VERSION 5.7 ;
  NOWIREEXTENSIONATPIN ON ;
  DIVIDERCHAR "/" ;
  BUSBITCHARS "[]" ;
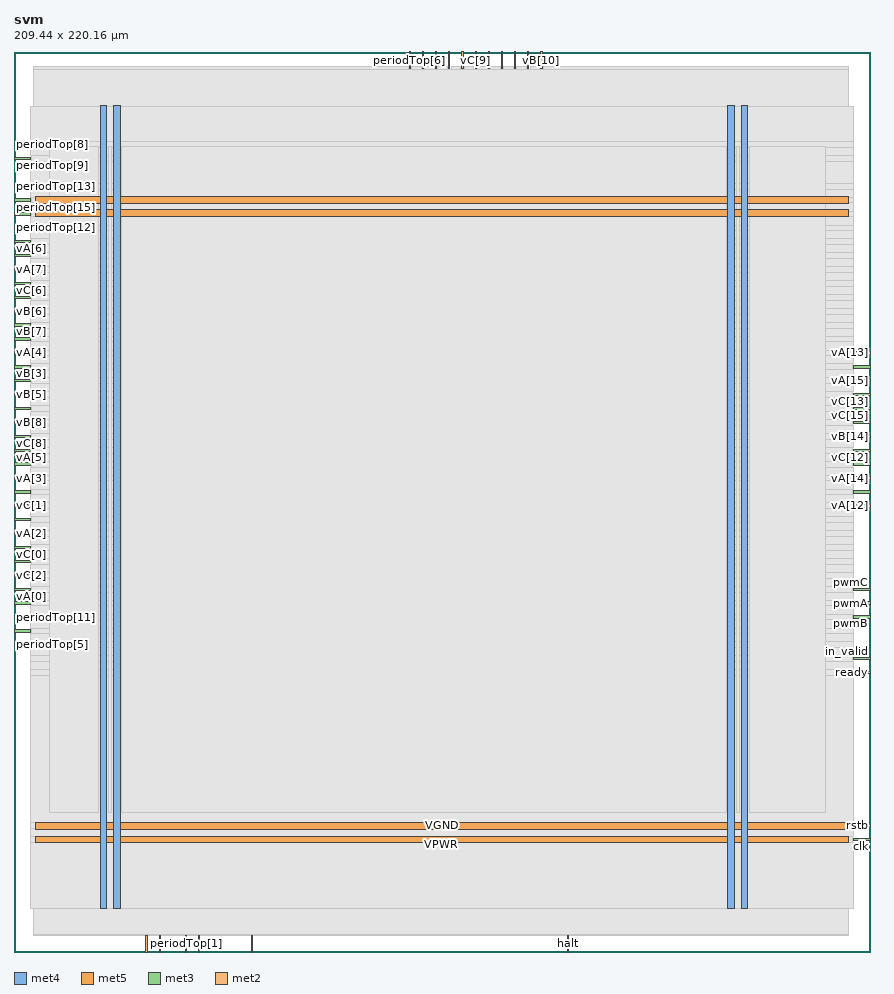
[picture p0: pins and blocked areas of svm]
MACRO svm
  CLASS BLOCK ;
  FOREIGN svm ;
  ORIGIN 0.000 0.000 ;
  SIZE 209.440 BY 220.160 ;
  PIN VGND
    DIRECTION INOUT ;
    USE GROUND ;
    PORT
      LAYER met4 ;
        RECT 24.340 10.640 25.940 206.960 ;
    END
    PORT
      LAYER met4 ;
        RECT 177.940 10.640 179.540 206.960 ;
    END
    PORT
      LAYER met5 ;
        RECT 5.280 30.030 204.020 31.630 ;
    END
    PORT
      LAYER met5 ;
        RECT 5.280 183.210 204.020 184.810 ;
    END
  END VGND
  PIN VPWR
    DIRECTION INOUT ;
    USE POWER ;
    PORT
      LAYER met4 ;
        RECT 21.040 10.640 22.640 206.960 ;
    END
    PORT
      LAYER met4 ;
        RECT 174.640 10.640 176.240 206.960 ;
    END
    PORT
      LAYER met5 ;
        RECT 5.280 26.730 204.020 28.330 ;
    END
    PORT
      LAYER met5 ;
        RECT 5.280 179.910 204.020 181.510 ;
    END
  END VPWR
  PIN clk
    DIRECTION INPUT ;
    USE SIGNAL ;
    ANTENNAGATEAREA 0.852000 ;
    PORT
      LAYER met3 ;
        RECT 205.440 27.240 209.440 27.840 ;
    END
  END clk
  PIN halt
    DIRECTION OUTPUT ;
    USE SIGNAL ;
    ANTENNADIFFAREA 0.795200 ;
    PORT
      LAYER met2 ;
        RECT 135.330 0.000 135.610 4.000 ;
    END
  END halt
  PIN in_valid
    DIRECTION INPUT ;
    USE SIGNAL ;
    ANTENNAGATEAREA 0.196500 ;
    PORT
      LAYER met3 ;
        RECT 205.440 71.440 209.440 72.040 ;
    END
  END in_valid
  PIN periodTop[0]
    DIRECTION INPUT ;
    USE SIGNAL ;
    ANTENNAGATEAREA 0.213000 ;
    PORT
      LAYER met2 ;
        RECT 58.050 0.000 58.330 4.000 ;
    END
  END periodTop[0]
  PIN periodTop[10]
    DIRECTION INPUT ;
    USE SIGNAL ;
    ANTENNAGATEAREA 0.159000 ;
    PORT
      LAYER met3 ;
        RECT 0.000 78.240 4.000 78.840 ;
    END
  END periodTop[10]
  PIN periodTop[11]
    DIRECTION INPUT ;
    USE SIGNAL ;
    ANTENNAGATEAREA 0.213000 ;
    PORT
      LAYER met3 ;
        RECT 0.000 81.640 4.000 82.240 ;
    END
  END periodTop[11]
  PIN periodTop[12]
    DIRECTION INPUT ;
    USE SIGNAL ;
    ANTENNAGATEAREA 0.196500 ;
    PORT
      LAYER met3 ;
        RECT 0.000 176.840 4.000 177.440 ;
    END
  END periodTop[12]
  PIN periodTop[13]
    DIRECTION INPUT ;
    USE SIGNAL ;
    ANTENNAGATEAREA 0.213000 ;
    PORT
      LAYER met3 ;
        RECT 0.000 187.040 4.000 187.640 ;
    END
  END periodTop[13]
  PIN periodTop[14]
    DIRECTION INPUT ;
    USE SIGNAL ;
    ANTENNAGATEAREA 0.213000 ;
    PORT
      LAYER met3 ;
        RECT 0.000 183.640 4.000 184.240 ;
    END
  END periodTop[14]
  PIN periodTop[15]
    DIRECTION INPUT ;
    USE SIGNAL ;
    ANTENNAGATEAREA 0.196500 ;
    PORT
      LAYER met3 ;
        RECT 0.000 180.240 4.000 180.840 ;
    END
  END periodTop[15]
  PIN periodTop[1]
    DIRECTION INPUT ;
    USE SIGNAL ;
    ANTENNAGATEAREA 0.196500 ;
    PORT
      LAYER met2 ;
        RECT 41.950 0.000 42.230 4.000 ;
    END
  END periodTop[1]
  PIN periodTop[2]
    DIRECTION INPUT ;
    USE SIGNAL ;
    ANTENNAGATEAREA 0.196500 ;
    PORT
      LAYER met2 ;
        RECT 45.170 0.000 45.450 4.000 ;
    END
  END periodTop[2]
  PIN periodTop[3]
    DIRECTION INPUT ;
    USE SIGNAL ;
    ANTENNAGATEAREA 0.196500 ;
    PORT
      LAYER met2 ;
        RECT 35.510 0.000 35.790 4.000 ;
    END
  END periodTop[3]
  PIN periodTop[4]
    DIRECTION INPUT ;
    USE SIGNAL ;
    ANTENNAGATEAREA 0.159000 ;
    PORT
      LAYER met2 ;
        RECT 32.290 0.000 32.570 4.000 ;
    END
  END periodTop[4]
  PIN periodTop[5]
    DIRECTION INPUT ;
    USE SIGNAL ;
    ANTENNAGATEAREA 0.213000 ;
    PORT
      LAYER met3 ;
        RECT 0.000 74.840 4.000 75.440 ;
    END
  END periodTop[5]
  PIN periodTop[6]
    DIRECTION INPUT ;
    USE SIGNAL ;
    ANTENNAGATEAREA 0.126000 ;
    PORT
      LAYER met2 ;
        RECT 96.690 216.160 96.970 220.160 ;
    END
  END periodTop[6]
  PIN periodTop[7]
    DIRECTION INPUT ;
    USE SIGNAL ;
    ANTENNAGATEAREA 0.126000 ;
    PORT
      LAYER met2 ;
        RECT 99.910 216.160 100.190 220.160 ;
    END
  END periodTop[7]
  PIN periodTop[8]
    DIRECTION INPUT ;
    USE SIGNAL ;
    ANTENNAGATEAREA 0.126000 ;
    PORT
      LAYER met3 ;
        RECT 0.000 197.240 4.000 197.840 ;
    END
  END periodTop[8]
  PIN periodTop[9]
    DIRECTION INPUT ;
    USE SIGNAL ;
    ANTENNAGATEAREA 0.126000 ;
    PORT
      LAYER met3 ;
        RECT 0.000 193.840 4.000 194.440 ;
    END
  END periodTop[9]
  PIN pwmA
    DIRECTION OUTPUT ;
    USE SIGNAL ;
    ANTENNADIFFAREA 0.795200 ;
    PORT
      LAYER met3 ;
        RECT 205.440 85.040 209.440 85.640 ;
    END
  END pwmA
  PIN pwmB
    DIRECTION OUTPUT ;
    USE SIGNAL ;
    ANTENNADIFFAREA 0.795200 ;
    PORT
      LAYER met3 ;
        RECT 205.440 81.640 209.440 82.240 ;
    END
  END pwmB
  PIN pwmC
    DIRECTION OUTPUT ;
    USE SIGNAL ;
    ANTENNADIFFAREA 0.445500 ;
    PORT
      LAYER met3 ;
        RECT 205.440 88.440 209.440 89.040 ;
    END
  END pwmC
  PIN ready
    DIRECTION OUTPUT ;
    USE SIGNAL ;
    ANTENNADIFFAREA 0.795200 ;
    PORT
      LAYER met3 ;
        RECT 205.440 68.040 209.440 68.640 ;
    END
  END ready
  PIN rstb
    DIRECTION INPUT ;
    USE SIGNAL ;
    ANTENNAGATEAREA 0.196500 ;
    PORT
      LAYER met3 ;
        RECT 205.440 30.640 209.440 31.240 ;
    END
  END rstb
  PIN vA[0]
    DIRECTION INPUT ;
    USE SIGNAL ;
    ANTENNAGATEAREA 0.196500 ;
    PORT
      LAYER met3 ;
        RECT 0.000 85.040 4.000 85.640 ;
    END
  END vA[0]
  PIN vA[10]
    DIRECTION INPUT ;
    USE SIGNAL ;
    ANTENNAGATEAREA 0.196500 ;
    PORT
      LAYER met2 ;
        RECT 103.130 216.160 103.410 220.160 ;
    END
  END vA[10]
  PIN vA[11]
    DIRECTION INPUT ;
    USE SIGNAL ;
    ANTENNAGATEAREA 0.196500 ;
    PORT
      LAYER met2 ;
        RECT 116.010 216.160 116.290 220.160 ;
    END
  END vA[11]
  PIN vA[12]
    DIRECTION INPUT ;
    USE SIGNAL ;
    ANTENNAGATEAREA 0.196500 ;
    PORT
      LAYER met3 ;
        RECT 205.440 108.840 209.440 109.440 ;
    END
  END vA[12]
  PIN vA[13]
    DIRECTION INPUT ;
    USE SIGNAL ;
    ANTENNAGATEAREA 0.196500 ;
    PORT
      LAYER met3 ;
        RECT 205.440 146.240 209.440 146.840 ;
    END
  END vA[13]
  PIN vA[14]
    DIRECTION INPUT ;
    USE SIGNAL ;
    ANTENNAGATEAREA 0.196500 ;
    PORT
      LAYER met3 ;
        RECT 205.440 115.640 209.440 116.240 ;
    END
  END vA[14]
  PIN vA[15]
    DIRECTION INPUT ;
    USE SIGNAL ;
    ANTENNAGATEAREA 0.196500 ;
    PORT
      LAYER met3 ;
        RECT 205.440 139.440 209.440 140.040 ;
    END
  END vA[15]
  PIN vA[1]
    DIRECTION INPUT ;
    USE SIGNAL ;
    ANTENNAGATEAREA 0.196500 ;
    PORT
      LAYER met3 ;
        RECT 0.000 112.240 4.000 112.840 ;
    END
  END vA[1]
  PIN vA[2]
    DIRECTION INPUT ;
    USE SIGNAL ;
    ANTENNAGATEAREA 0.196500 ;
    PORT
      LAYER met3 ;
        RECT 0.000 102.040 4.000 102.640 ;
    END
  END vA[2]
  PIN vA[3]
    DIRECTION INPUT ;
    USE SIGNAL ;
    ANTENNAGATEAREA 0.196500 ;
    PORT
      LAYER met3 ;
        RECT 0.000 115.640 4.000 116.240 ;
    END
  END vA[3]
  PIN vA[4]
    DIRECTION INPUT ;
    USE SIGNAL ;
    ANTENNAGATEAREA 0.196500 ;
    PORT
      LAYER met3 ;
        RECT 0.000 146.240 4.000 146.840 ;
    END
  END vA[4]
  PIN vA[5]
    DIRECTION INPUT ;
    USE SIGNAL ;
    ANTENNAGATEAREA 0.196500 ;
    PORT
      LAYER met3 ;
        RECT 0.000 119.040 4.000 119.640 ;
    END
  END vA[5]
  PIN vA[6]
    DIRECTION INPUT ;
    USE SIGNAL ;
    ANTENNAGATEAREA 0.196500 ;
    PORT
      LAYER met3 ;
        RECT 0.000 173.440 4.000 174.040 ;
    END
  END vA[6]
  PIN vA[7]
    DIRECTION INPUT ;
    USE SIGNAL ;
    ANTENNAGATEAREA 0.196500 ;
    PORT
      LAYER met3 ;
        RECT 0.000 166.640 4.000 167.240 ;
    END
  END vA[7]
  PIN vA[8]
    DIRECTION INPUT ;
    USE SIGNAL ;
    ANTENNAGATEAREA 0.196500 ;
    PORT
      LAYER met3 ;
        RECT 0.000 122.440 4.000 123.040 ;
    END
  END vA[8]
  PIN vA[9]
    DIRECTION INPUT ;
    USE SIGNAL ;
    ANTENNAGATEAREA 0.196500 ;
    PORT
      LAYER met2 ;
        RECT 106.350 216.160 106.630 220.160 ;
    END
  END vA[9]
  PIN vB[0]
    DIRECTION INPUT ;
    USE SIGNAL ;
    ANTENNAGATEAREA 0.196500 ;
    PORT
      LAYER met3 ;
        RECT 0.000 88.440 4.000 89.040 ;
    END
  END vB[0]
  PIN vB[10]
    DIRECTION INPUT ;
    USE SIGNAL ;
    ANTENNAGATEAREA 0.196500 ;
    PORT
      LAYER met2 ;
        RECT 128.890 216.160 129.170 220.160 ;
    END
  END vB[10]
  PIN vB[11]
    DIRECTION INPUT ;
    USE SIGNAL ;
    ANTENNAGATEAREA 0.196500 ;
    PORT
      LAYER met2 ;
        RECT 119.230 216.160 119.510 220.160 ;
    END
  END vB[11]
  PIN vB[12]
    DIRECTION INPUT ;
    USE SIGNAL ;
    ANTENNAGATEAREA 0.196500 ;
    PORT
      LAYER met3 ;
        RECT 205.440 112.240 209.440 112.840 ;
    END
  END vB[12]
  PIN vB[13]
    DIRECTION INPUT ;
    USE SIGNAL ;
    ANTENNAGATEAREA 0.196500 ;
    PORT
      LAYER met3 ;
        RECT 205.440 142.840 209.440 143.440 ;
    END
  END vB[13]
  PIN vB[14]
    DIRECTION INPUT ;
    USE SIGNAL ;
    ANTENNAGATEAREA 0.196500 ;
    PORT
      LAYER met3 ;
        RECT 205.440 125.840 209.440 126.440 ;
    END
  END vB[14]
  PIN vB[15]
    DIRECTION INPUT ;
    USE SIGNAL ;
    ANTENNAGATEAREA 0.196500 ;
    PORT
      LAYER met3 ;
        RECT 205.440 132.640 209.440 133.240 ;
    END
  END vB[15]
  PIN vB[1]
    DIRECTION INPUT ;
    USE SIGNAL ;
    ANTENNAGATEAREA 0.196500 ;
    PORT
      LAYER met3 ;
        RECT 0.000 105.440 4.000 106.040 ;
    END
  END vB[1]
  PIN vB[2]
    DIRECTION INPUT ;
    USE SIGNAL ;
    ANTENNAGATEAREA 0.196500 ;
    PORT
      LAYER met3 ;
        RECT 0.000 95.240 4.000 95.840 ;
    END
  END vB[2]
  PIN vB[3]
    DIRECTION INPUT ;
    USE SIGNAL ;
    ANTENNAGATEAREA 0.196500 ;
    PORT
      LAYER met3 ;
        RECT 0.000 142.840 4.000 143.440 ;
    END
  END vB[3]
  PIN vB[4]
    DIRECTION INPUT ;
    USE SIGNAL ;
    ANTENNAGATEAREA 0.196500 ;
    PORT
      LAYER met3 ;
        RECT 0.000 170.040 4.000 170.640 ;
    END
  END vB[4]
  PIN vB[5]
    DIRECTION INPUT ;
    USE SIGNAL ;
    ANTENNAGATEAREA 0.196500 ;
    PORT
      LAYER met3 ;
        RECT 0.000 136.040 4.000 136.640 ;
    END
  END vB[5]
  PIN vB[6]
    DIRECTION INPUT ;
    USE SIGNAL ;
    ANTENNAGATEAREA 0.196500 ;
    PORT
      LAYER met3 ;
        RECT 0.000 156.440 4.000 157.040 ;
    END
  END vB[6]
  PIN vB[7]
    DIRECTION INPUT ;
    USE SIGNAL ;
    ANTENNAGATEAREA 0.196500 ;
    PORT
      LAYER met3 ;
        RECT 0.000 153.040 4.000 153.640 ;
    END
  END vB[7]
  PIN vB[8]
    DIRECTION INPUT ;
    USE SIGNAL ;
    ANTENNAGATEAREA 0.196500 ;
    PORT
      LAYER met3 ;
        RECT 0.000 129.240 4.000 129.840 ;
    END
  END vB[8]
  PIN vB[9]
    DIRECTION INPUT ;
    USE SIGNAL ;
    ANTENNAGATEAREA 0.196500 ;
    PORT
      LAYER met2 ;
        RECT 109.570 216.160 109.850 220.160 ;
    END
  END vB[9]
  PIN vC[0]
    DIRECTION INPUT ;
    USE SIGNAL ;
    ANTENNAGATEAREA 0.495000 ;
    PORT
      LAYER met3 ;
        RECT 0.000 98.640 4.000 99.240 ;
    END
  END vC[0]
  PIN vC[10]
    DIRECTION INPUT ;
    USE SIGNAL ;
    ANTENNAGATEAREA 0.495000 ;
    PORT
      LAYER met2 ;
        RECT 122.450 216.160 122.730 220.160 ;
    END
  END vC[10]
  PIN vC[11]
    DIRECTION INPUT ;
    USE SIGNAL ;
    ANTENNAGATEAREA 0.196500 ;
    PORT
      LAYER met2 ;
        RECT 125.670 216.160 125.950 220.160 ;
    END
  END vC[11]
  PIN vC[12]
    DIRECTION INPUT ;
    USE SIGNAL ;
    ANTENNAGATEAREA 0.196500 ;
    PORT
      LAYER met3 ;
        RECT 205.440 119.040 209.440 119.640 ;
    END
  END vC[12]
  PIN vC[13]
    DIRECTION INPUT ;
    USE SIGNAL ;
    ANTENNAGATEAREA 0.196500 ;
    PORT
      LAYER met3 ;
        RECT 205.440 136.040 209.440 136.640 ;
    END
  END vC[13]
  PIN vC[14]
    DIRECTION INPUT ;
    USE SIGNAL ;
    ANTENNAGATEAREA 0.196500 ;
    PORT
      LAYER met3 ;
        RECT 205.440 122.440 209.440 123.040 ;
    END
  END vC[14]
  PIN vC[15]
    DIRECTION INPUT ;
    USE SIGNAL ;
    ANTENNAGATEAREA 0.196500 ;
    PORT
      LAYER met3 ;
        RECT 205.440 129.240 209.440 129.840 ;
    END
  END vC[15]
  PIN vC[1]
    DIRECTION INPUT ;
    USE SIGNAL ;
    ANTENNAGATEAREA 0.196500 ;
    PORT
      LAYER met3 ;
        RECT 0.000 108.840 4.000 109.440 ;
    END
  END vC[1]
  PIN vC[2]
    DIRECTION INPUT ;
    USE SIGNAL ;
    ANTENNAGATEAREA 0.196500 ;
    PORT
      LAYER met3 ;
        RECT 0.000 91.840 4.000 92.440 ;
    END
  END vC[2]
  PIN vC[3]
    DIRECTION INPUT ;
    USE SIGNAL ;
    ANTENNAGATEAREA 0.196500 ;
    PORT
      LAYER met3 ;
        RECT 0.000 139.440 4.000 140.040 ;
    END
  END vC[3]
  PIN vC[4]
    DIRECTION INPUT ;
    USE SIGNAL ;
    ANTENNAGATEAREA 0.495000 ;
    PORT
      LAYER met3 ;
        RECT 0.000 149.640 4.000 150.240 ;
    END
  END vC[4]
  PIN vC[5]
    DIRECTION INPUT ;
    USE SIGNAL ;
    ANTENNAGATEAREA 0.196500 ;
    PORT
      LAYER met3 ;
        RECT 0.000 132.640 4.000 133.240 ;
    END
  END vC[5]
  PIN vC[6]
    DIRECTION INPUT ;
    USE SIGNAL ;
    ANTENNAGATEAREA 0.196500 ;
    PORT
      LAYER met3 ;
        RECT 0.000 159.840 4.000 160.440 ;
    END
  END vC[6]
  PIN vC[7]
    DIRECTION INPUT ;
    USE SIGNAL ;
    ANTENNAGATEAREA 0.196500 ;
    PORT
      LAYER met3 ;
        RECT 0.000 163.240 4.000 163.840 ;
    END
  END vC[7]
  PIN vC[8]
    DIRECTION INPUT ;
    USE SIGNAL ;
    ANTENNAGATEAREA 0.196500 ;
    PORT
      LAYER met3 ;
        RECT 0.000 125.840 4.000 126.440 ;
    END
  END vC[8]
  PIN vC[9]
    DIRECTION INPUT ;
    USE SIGNAL ;
    ANTENNAGATEAREA 0.495000 ;
    PORT
      LAYER met2 ;
        RECT 112.790 216.160 113.070 220.160 ;
    END
  END vC[9]
  OBS
      LAYER li1 ;
        RECT 5.520 10.795 203.780 206.805 ;
      LAYER met1 ;
        RECT 4.670 10.640 204.170 206.960 ;
      LAYER met2 ;
        RECT 4.690 215.880 96.410 216.650 ;
        RECT 97.250 215.880 99.630 216.650 ;
        RECT 100.470 215.880 102.850 216.650 ;
        RECT 103.690 215.880 106.070 216.650 ;
        RECT 106.910 215.880 109.290 216.650 ;
        RECT 110.130 215.880 112.510 216.650 ;
        RECT 113.350 215.880 115.730 216.650 ;
        RECT 116.570 215.880 118.950 216.650 ;
        RECT 119.790 215.880 122.170 216.650 ;
        RECT 123.010 215.880 125.390 216.650 ;
        RECT 126.230 215.880 128.610 216.650 ;
        RECT 129.450 215.880 204.150 216.650 ;
        RECT 4.690 4.280 204.150 215.880 ;
        RECT 4.690 4.000 32.010 4.280 ;
        RECT 32.850 4.000 35.230 4.280 ;
        RECT 36.070 4.000 41.670 4.280 ;
        RECT 42.510 4.000 44.890 4.280 ;
        RECT 45.730 4.000 57.770 4.280 ;
        RECT 58.610 4.000 135.050 4.280 ;
        RECT 135.890 4.000 204.150 4.280 ;
      LAYER met3 ;
        RECT 3.990 198.240 205.440 206.885 ;
        RECT 4.400 196.840 205.440 198.240 ;
        RECT 3.990 194.840 205.440 196.840 ;
        RECT 4.400 193.440 205.440 194.840 ;
        RECT 3.990 188.040 205.440 193.440 ;
        RECT 4.400 186.640 205.440 188.040 ;
        RECT 3.990 184.640 205.440 186.640 ;
        RECT 4.400 183.240 205.440 184.640 ;
        RECT 3.990 181.240 205.440 183.240 ;
        RECT 4.400 179.840 205.440 181.240 ;
        RECT 3.990 177.840 205.440 179.840 ;
        RECT 4.400 176.440 205.440 177.840 ;
        RECT 3.990 174.440 205.440 176.440 ;
        RECT 4.400 173.040 205.440 174.440 ;
        RECT 3.990 171.040 205.440 173.040 ;
        RECT 4.400 169.640 205.440 171.040 ;
        RECT 3.990 167.640 205.440 169.640 ;
        RECT 4.400 166.240 205.440 167.640 ;
        RECT 3.990 164.240 205.440 166.240 ;
        RECT 4.400 162.840 205.440 164.240 ;
        RECT 3.990 160.840 205.440 162.840 ;
        RECT 4.400 159.440 205.440 160.840 ;
        RECT 3.990 157.440 205.440 159.440 ;
        RECT 4.400 156.040 205.440 157.440 ;
        RECT 3.990 154.040 205.440 156.040 ;
        RECT 4.400 152.640 205.440 154.040 ;
        RECT 3.990 150.640 205.440 152.640 ;
        RECT 4.400 149.240 205.440 150.640 ;
        RECT 3.990 147.240 205.440 149.240 ;
        RECT 4.400 145.840 205.040 147.240 ;
        RECT 3.990 143.840 205.440 145.840 ;
        RECT 4.400 142.440 205.040 143.840 ;
        RECT 3.990 140.440 205.440 142.440 ;
        RECT 4.400 139.040 205.040 140.440 ;
        RECT 3.990 137.040 205.440 139.040 ;
        RECT 4.400 135.640 205.040 137.040 ;
        RECT 3.990 133.640 205.440 135.640 ;
        RECT 4.400 132.240 205.040 133.640 ;
        RECT 3.990 130.240 205.440 132.240 ;
        RECT 4.400 128.840 205.040 130.240 ;
        RECT 3.990 126.840 205.440 128.840 ;
        RECT 4.400 125.440 205.040 126.840 ;
        RECT 3.990 123.440 205.440 125.440 ;
        RECT 4.400 122.040 205.040 123.440 ;
        RECT 3.990 120.040 205.440 122.040 ;
        RECT 4.400 118.640 205.040 120.040 ;
        RECT 3.990 116.640 205.440 118.640 ;
        RECT 4.400 115.240 205.040 116.640 ;
        RECT 3.990 113.240 205.440 115.240 ;
        RECT 4.400 111.840 205.040 113.240 ;
        RECT 3.990 109.840 205.440 111.840 ;
        RECT 4.400 108.440 205.040 109.840 ;
        RECT 3.990 106.440 205.440 108.440 ;
        RECT 4.400 105.040 205.440 106.440 ;
        RECT 3.990 103.040 205.440 105.040 ;
        RECT 4.400 101.640 205.440 103.040 ;
        RECT 3.990 99.640 205.440 101.640 ;
        RECT 4.400 98.240 205.440 99.640 ;
        RECT 3.990 96.240 205.440 98.240 ;
        RECT 4.400 94.840 205.440 96.240 ;
        RECT 3.990 92.840 205.440 94.840 ;
        RECT 4.400 91.440 205.440 92.840 ;
        RECT 3.990 89.440 205.440 91.440 ;
        RECT 4.400 88.040 205.040 89.440 ;
        RECT 3.990 86.040 205.440 88.040 ;
        RECT 4.400 84.640 205.040 86.040 ;
        RECT 3.990 82.640 205.440 84.640 ;
        RECT 4.400 81.240 205.040 82.640 ;
        RECT 3.990 79.240 205.440 81.240 ;
        RECT 4.400 77.840 205.440 79.240 ;
        RECT 3.990 75.840 205.440 77.840 ;
        RECT 4.400 74.440 205.440 75.840 ;
        RECT 3.990 72.440 205.440 74.440 ;
        RECT 3.990 71.040 205.040 72.440 ;
        RECT 3.990 69.040 205.440 71.040 ;
        RECT 3.990 67.640 205.040 69.040 ;
        RECT 3.990 31.640 205.440 67.640 ;
        RECT 3.990 30.240 205.040 31.640 ;
        RECT 3.990 28.240 205.440 30.240 ;
        RECT 3.990 26.840 205.040 28.240 ;
        RECT 3.990 10.715 205.440 26.840 ;
      LAYER met4 ;
        RECT 8.575 34.175 20.640 197.025 ;
        RECT 23.040 34.175 23.940 197.025 ;
        RECT 26.340 34.175 174.240 197.025 ;
        RECT 176.640 34.175 177.540 197.025 ;
        RECT 179.940 34.175 198.425 197.025 ;
  END
END svm
END LIBRARY

